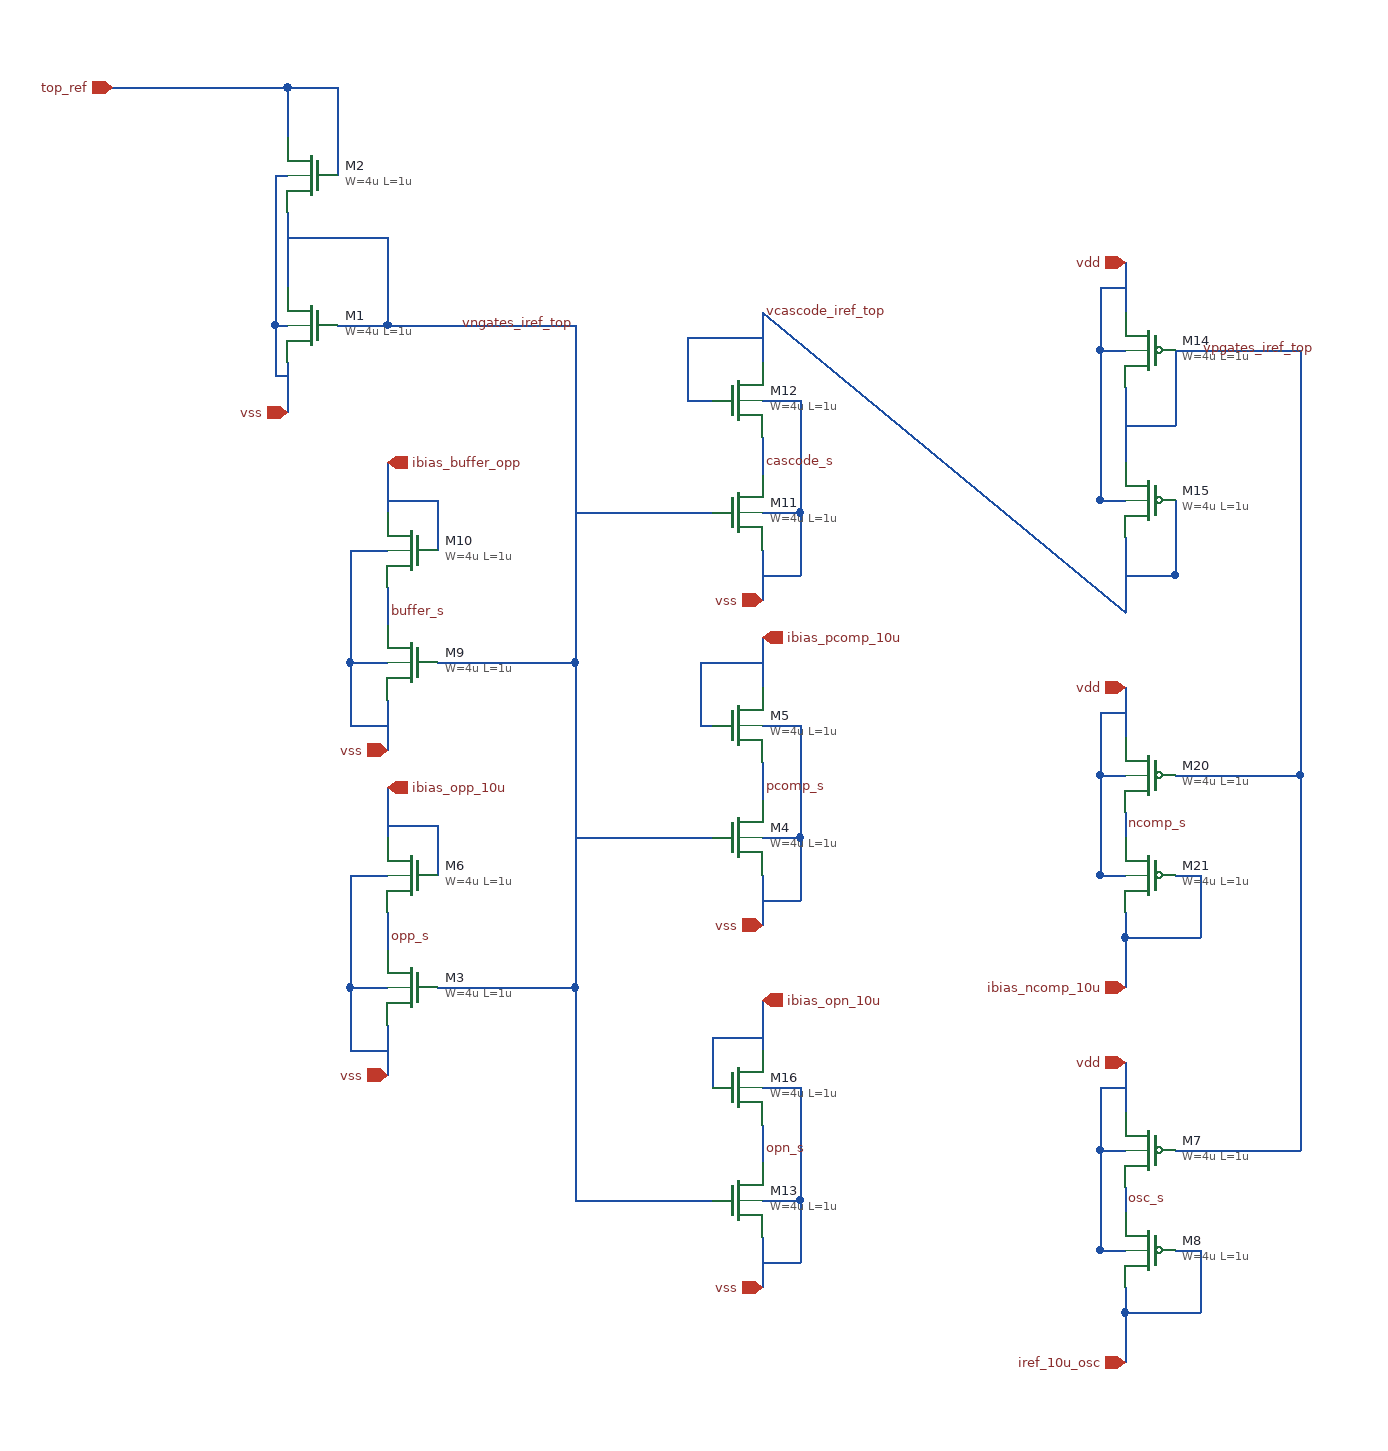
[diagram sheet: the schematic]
v {xschem version=3.4.7 file_version=1.2}
G {}
K {}
V {}
S {}
E {}
N 180 -1170 210 -1170 {lab=top_ref}
N 210 -1170 320 -1170 {lab=top_ref}
N 310 -980 320 -980 {lab=vss}
N 320 -950 320 -920 {lab=vss}
N 310 -980 310 -940 {lab=vss}
N 310 -940 320 -940 {lab=vss}
N 320 -920 320 -910 {lab=vss}
N 360 -980 400 -980 {lab=vngates_iref_top}
N 320 -1050 400 -1050 {lab=vngates_iref_top}
N 320 -1070 320 -1010 {lab=vngates_iref_top}
N 310 -1100 320 -1100 {lab=vss}
N 310 -1100 310 -980 {lab=vss}
N 320 -1170 320 -1130 {lab=top_ref}
N 360 -1170 360 -1100 {lab=top_ref}
N 320 -1170 360 -1170 {lab=top_ref}
N 700 -540 700 -500 {lab=vss}
N 700 -570 730 -570 {lab=vss}
N 730 -570 730 -520 {lab=vss}
N 700 -520 730 -520 {lab=vss}
N 700 -630 700 -600 {lab=pcomp_s}
N 620 -570 660 -570 {lab=vngates_iref_top}
N 700 -730 700 -690 {lab=ibias_pcomp_10u}
N 710 -660 730 -660 {lab=vss}
N 730 -660 730 -570 {lab=vss}
N 700 -660 710 -660 {lab=vss}
N 400 -420 400 -380 {lab=vss}
N 370 -450 400 -450 {lab=vss}
N 370 -450 370 -400 {lab=vss}
N 370 -400 400 -400 {lab=vss}
N 400 -510 400 -480 {lab=opp_s}
N 440 -450 480 -450 {lab=vngates_iref_top}
N 400 -610 400 -570 {lab=ibias_opp_10u}
N 370 -540 390 -540 {lab=vss}
N 370 -540 370 -450 {lab=vss}
N 390 -540 400 -540 {lab=vss}
N 400 -680 400 -640 {lab=vss}
N 370 -710 400 -710 {lab=vss}
N 370 -710 370 -660 {lab=vss}
N 370 -660 400 -660 {lab=vss}
N 400 -770 400 -740 {lab=buffer_s}
N 510 -710 550 -710 {lab=vngates_iref_top}
N 370 -800 390 -800 {lab=vss}
N 370 -800 370 -710 {lab=vss}
N 390 -800 400 -800 {lab=vss}
N 400 -870 400 -830 {lab=ibias_buffer_opp}
N 550 -980 550 -710 {lab=vngates_iref_top}
N 550 -710 550 -450 {lab=vngates_iref_top}
N 700 -800 700 -760 {lab=vss}
N 700 -830 730 -830 {lab=vss}
N 730 -830 730 -780 {lab=vss}
N 700 -780 730 -780 {lab=vss}
N 700 -890 700 -860 {lab=cascode_s}
N 620 -830 660 -830 {lab=vngates_iref_top}
N 710 -920 730 -920 {lab=vss}
N 730 -920 730 -830 {lab=vss}
N 700 -920 710 -920 {lab=vss}
N 700 -990 700 -940 {lab=vcascode_iref_top}
N 990 -780 1030 -780 {lab=vcascode_iref_top}
N 1030 -840 1030 -780 {lab=vcascode_iref_top}
N 970 -840 990 -840 {lab=vdd}
N 990 -900 1030 -900 {lab=vpgates_iref_top}
N 1030 -960 1030 -900 {lab=vpgates_iref_top}
N 970 -960 990 -960 {lab=vdd}
N 970 -1010 970 -960 {lab=vdd}
N 970 -1010 980 -1010 {lab=vdd}
N 980 -1010 990 -1010 {lab=vdd}
N 990 -1030 990 -990 {lab=vdd}
N 990 -930 990 -870 {lab=vpgates_iref_top}
N 970 -960 970 -890 {lab=vdd}
N 1030 -960 1130 -960 {lab=vpgates_iref_top}
N 990 -810 990 -750 {lab=vcascode_iref_top}
N 990 -780 1030 -780 {lab=vcascode_iref_top}
N 1030 -840 1030 -780 {lab=vcascode_iref_top}
N 970 -840 990 -840 {lab=vdd}
N 970 -890 970 -840 {lab=vdd}
N 990 -930 990 -870 {lab=vpgates_iref_top}
N 1130 -960 1130 -620 {lab=vpgates_iref_top}
N 970 -540 990 -540 {lab=vdd}
N 970 -620 990 -620 {lab=vdd}
N 970 -670 970 -620 {lab=vdd}
N 970 -670 980 -670 {lab=vdd}
N 980 -670 990 -670 {lab=vdd}
N 990 -690 990 -650 {lab=vdd}
N 1030 -620 1130 -620 {lab=vpgates_iref_top}
N 970 -540 990 -540 {lab=vdd}
N 990 -590 990 -580 {lab=cascode_s}
N 990 -580 990 -570 {lab=cascode_s}
N 970 -620 970 -540 {lab=vdd}
N 1030 -540 1050 -540 {lab=ibias_ncomp_10u}
N 1050 -540 1050 -490 {lab=ibias_ncomp_10u}
N 990 -490 1050 -490 {lab=ibias_ncomp_10u}
N 990 -510 990 -490 {lab=ibias_ncomp_10u}
N 990 -490 990 -450 {lab=ibias_ncomp_10u}
N 640 -920 660 -920 {lab=vcascode_iref_top}
N 640 -970 640 -920 {lab=vcascode_iref_top}
N 640 -970 700 -970 {lab=vcascode_iref_top}
N 650 -660 660 -660 {lab=ibias_pcomp_10u}
N 650 -710 650 -660 {lab=ibias_pcomp_10u}
N 650 -710 700 -710 {lab=ibias_pcomp_10u}
N 440 -840 440 -800 {lab=ibias_buffer_opp}
N 400 -840 440 -840 {lab=ibias_buffer_opp}
N 440 -580 440 -540 {lab=ibias_opp_10u}
N 400 -580 440 -580 {lab=ibias_opp_10u}
N 400 -1050 400 -980 {lab=vngates_iref_top}
N 400 -980 480 -980 {lab=vngates_iref_top}
N 500 -710 510 -710 {lab=vngates_iref_top}
N 440 -710 500 -710 {lab=vngates_iref_top}
N 480 -450 550 -450 {lab=vngates_iref_top}
N 550 -450 550 -310 {lab=vngates_iref_top}
N 550 -570 620 -570 {lab=vngates_iref_top}
N 550 -830 620 -830 {lab=vngates_iref_top}
N 480 -980 550 -980 {lab=vngates_iref_top}
N 700 -250 700 -210 {lab=vss}
N 700 -280 730 -280 {lab=vss}
N 730 -280 730 -230 {lab=vss}
N 700 -230 730 -230 {lab=vss}
N 700 -340 700 -310 {lab=opn_s}
N 620 -280 660 -280 {lab=vngates_iref_top}
N 700 -440 700 -400 {lab=ibias_opn_10u}
N 710 -370 730 -370 {lab=vss}
N 730 -370 730 -280 {lab=vss}
N 700 -370 710 -370 {lab=vss}
N 660 -410 660 -370 {lab=ibias_opn_10u}
N 660 -410 700 -410 {lab=ibias_opn_10u}
N 550 -280 620 -280 {lab=vngates_iref_top}
N 550 -300 550 -280 {lab=vngates_iref_top}
N 550 -310 550 -300 {lab=vngates_iref_top}
N 970 -240 990 -240 {lab=vdd}
N 970 -320 990 -320 {lab=vdd}
N 970 -370 970 -320 {lab=vdd}
N 970 -370 980 -370 {lab=vdd}
N 980 -370 990 -370 {lab=vdd}
N 990 -390 990 -350 {lab=vdd}
N 1030 -320 1130 -320 {lab=vpgates_iref_top}
N 970 -240 990 -240 {lab=vdd}
N 990 -290 990 -280 {lab=#net1}
N 990 -280 990 -270 {lab=#net1}
N 970 -320 970 -240 {lab=vdd}
N 1030 -240 1050 -240 {lab=iref_10u_osc}
N 1050 -240 1050 -190 {lab=iref_10u_osc}
N 990 -190 1050 -190 {lab=iref_10u_osc}
N 990 -210 990 -190 {lab=iref_10u_osc}
N 990 -190 990 -150 {lab=iref_10u_osc}
N 1130 -620 1130 -320 {lab=vpgates_iref_top}
N 700 -990 990 -750 {lab=vcascode_iref_top}
C {title.sym} 160 30 0 0 {name=l1 author="Christopher O Amankwaa"}
C {symbols/nfet_03v3.sym} 340 -980 0 1 {name=M1
L=1u
W=4u
nf=1
m=1
ad="'int((nf+1)/2) * W/nf * 0.18u'"
pd="'2*int((nf+1)/2) * (W/nf + 0.18u)'"
as="'int((nf+2)/2) * W/nf * 0.18u'"
ps="'2*int((nf+2)/2) * (W/nf + 0.18u)'"
nrd="'0.18u / W'" nrs="'0.18u / W'"
sa=0 sb=0 sd=0
model=nfet_03v3
spiceprefix=X
}
C {symbols/nfet_03v3.sym} 340 -1100 0 1 {name=M2
L=1u
W=4u
nf=1
m=1
ad="'int((nf+1)/2) * W/nf * 0.18u'"
pd="'2*int((nf+1)/2) * (W/nf + 0.18u)'"
as="'int((nf+2)/2) * W/nf * 0.18u'"
ps="'2*int((nf+2)/2) * (W/nf + 0.18u)'"
nrd="'0.18u / W'" nrs="'0.18u / W'"
sa=0 sb=0 sd=0
model=nfet_03v3
spiceprefix=X
}
C {lab_wire.sym} 550 -980 0 0 {name=p116 sig_type=std_logic lab=vngates_iref_top}
C {symbols/nfet_03v3.sym} 680 -570 0 0 {name=M4
L=1u
W=4u
nf=1
m=1
ad="'int((nf+1)/2) * W/nf * 0.18u'"
pd="'2*int((nf+1)/2) * (W/nf + 0.18u)'"
as="'int((nf+2)/2) * W/nf * 0.18u'"
ps="'2*int((nf+2)/2) * (W/nf + 0.18u)'"
nrd="'0.18u / W'" nrs="'0.18u / W'"
sa=0 sb=0 sd=0
model=nfet_03v3
spiceprefix=X
}
C {symbols/nfet_03v3.sym} 680 -660 0 0 {name=M5
L=1u
W=4u
nf=1
m=1
ad="'int((nf+1)/2) * W/nf * 0.18u'"
pd="'2*int((nf+1)/2) * (W/nf + 0.18u)'"
as="'int((nf+2)/2) * W/nf * 0.18u'"
ps="'2*int((nf+2)/2) * (W/nf + 0.18u)'"
nrd="'0.18u / W'" nrs="'0.18u / W'"
sa=0 sb=0 sd=0
model=nfet_03v3
spiceprefix=X
}
C {symbols/nfet_03v3.sym} 420 -450 0 1 {name=M3
L=1u
W=4u
nf=1
m=1
ad="'int((nf+1)/2) * W/nf * 0.18u'"
pd="'2*int((nf+1)/2) * (W/nf + 0.18u)'"
as="'int((nf+2)/2) * W/nf * 0.18u'"
ps="'2*int((nf+2)/2) * (W/nf + 0.18u)'"
nrd="'0.18u / W'" nrs="'0.18u / W'"
sa=0 sb=0 sd=0
model=nfet_03v3
spiceprefix=X
}
C {symbols/nfet_03v3.sym} 420 -540 0 1 {name=M6
L=1u
W=4u
nf=1
m=1
ad="'int((nf+1)/2) * W/nf * 0.18u'"
pd="'2*int((nf+1)/2) * (W/nf + 0.18u)'"
as="'int((nf+2)/2) * W/nf * 0.18u'"
ps="'2*int((nf+2)/2) * (W/nf + 0.18u)'"
nrd="'0.18u / W'" nrs="'0.18u / W'"
sa=0 sb=0 sd=0
model=nfet_03v3
spiceprefix=X
}
C {symbols/nfet_03v3.sym} 420 -710 0 1 {name=M9
L=1u
W=4u
nf=1
m=1
ad="'int((nf+1)/2) * W/nf * 0.18u'"
pd="'2*int((nf+1)/2) * (W/nf + 0.18u)'"
as="'int((nf+2)/2) * W/nf * 0.18u'"
ps="'2*int((nf+2)/2) * (W/nf + 0.18u)'"
nrd="'0.18u / W'" nrs="'0.18u / W'"
sa=0 sb=0 sd=0
model=nfet_03v3
spiceprefix=X
}
C {symbols/nfet_03v3.sym} 420 -800 0 1 {name=M10
L=1u
W=4u
nf=1
m=1
ad="'int((nf+1)/2) * W/nf * 0.18u'"
pd="'2*int((nf+1)/2) * (W/nf + 0.18u)'"
as="'int((nf+2)/2) * W/nf * 0.18u'"
ps="'2*int((nf+2)/2) * (W/nf + 0.18u)'"
nrd="'0.18u / W'" nrs="'0.18u / W'"
sa=0 sb=0 sd=0
model=nfet_03v3
spiceprefix=X
}
C {symbols/nfet_03v3.sym} 680 -830 0 0 {name=M11
L=1u
W=4u
nf=1
m=1
ad="'int((nf+1)/2) * W/nf * 0.18u'"
pd="'2*int((nf+1)/2) * (W/nf + 0.18u)'"
as="'int((nf+2)/2) * W/nf * 0.18u'"
ps="'2*int((nf+2)/2) * (W/nf + 0.18u)'"
nrd="'0.18u / W'" nrs="'0.18u / W'"
sa=0 sb=0 sd=0
model=nfet_03v3
spiceprefix=X
}
C {symbols/nfet_03v3.sym} 680 -920 0 0 {name=M12
L=1u
W=4u
nf=1
m=1
ad="'int((nf+1)/2) * W/nf * 0.18u'"
pd="'2*int((nf+1)/2) * (W/nf + 0.18u)'"
as="'int((nf+2)/2) * W/nf * 0.18u'"
ps="'2*int((nf+2)/2) * (W/nf + 0.18u)'"
nrd="'0.18u / W'" nrs="'0.18u / W'"
sa=0 sb=0 sd=0
model=nfet_03v3
spiceprefix=X
}
C {symbols/pfet_03v3.sym} 1010 -960 0 1 {name=M14
L=1u
W=4u
nf=1
m=1
ad="'int((nf+1)/2) * W/nf * 0.18u'"
pd="'2*int((nf+1)/2) * (W/nf + 0.18u)'"
as="'int((nf+2)/2) * W/nf * 0.18u'"
ps="'2*int((nf+2)/2) * (W/nf + 0.18u)'"
nrd="'0.18u / W'" nrs="'0.18u / W'"
sa=0 sb=0 sd=0
model=pfet_03v3
spiceprefix=X
}
C {lab_wire.sym} 700 -990 0 1 {name=p126 sig_type=std_logic lab=vcascode_iref_top}
C {lab_wire.sym} 1050 -960 0 1 {name=p127 sig_type=std_logic lab=vpgates_iref_top}
C {symbols/pfet_03v3.sym} 1010 -840 0 1 {name=M15
L=1u
W=4u
nf=1
m=1
ad="'int((nf+1)/2) * W/nf * 0.18u'"
pd="'2*int((nf+1)/2) * (W/nf + 0.18u)'"
as="'int((nf+2)/2) * W/nf * 0.18u'"
ps="'2*int((nf+2)/2) * (W/nf + 0.18u)'"
nrd="'0.18u / W'" nrs="'0.18u / W'"
sa=0 sb=0 sd=0
model=pfet_03v3
spiceprefix=X
}
C {symbols/pfet_03v3.sym} 1010 -620 0 1 {name=M20
L=1u
W=4u
nf=1
m=1
ad="'int((nf+1)/2) * W/nf * 0.18u'"
pd="'2*int((nf+1)/2) * (W/nf + 0.18u)'"
as="'int((nf+2)/2) * W/nf * 0.18u'"
ps="'2*int((nf+2)/2) * (W/nf + 0.18u)'"
nrd="'0.18u / W'" nrs="'0.18u / W'"
sa=0 sb=0 sd=0
model=pfet_03v3
spiceprefix=X
}
C {symbols/pfet_03v3.sym} 1010 -540 0 1 {name=M21
L=1u
W=4u
nf=1
m=1
ad="'int((nf+1)/2) * W/nf * 0.18u'"
pd="'2*int((nf+1)/2) * (W/nf + 0.18u)'"
as="'int((nf+2)/2) * W/nf * 0.18u'"
ps="'2*int((nf+2)/2) * (W/nf + 0.18u)'"
nrd="'0.18u / W'" nrs="'0.18u / W'"
sa=0 sb=0 sd=0
model=pfet_03v3
spiceprefix=X
}
C {symbols/nfet_03v3.sym} 680 -280 0 0 {name=M13
L=1u
W=4u
nf=1
m=1
ad="'int((nf+1)/2) * W/nf * 0.18u'"
pd="'2*int((nf+1)/2) * (W/nf + 0.18u)'"
as="'int((nf+2)/2) * W/nf * 0.18u'"
ps="'2*int((nf+2)/2) * (W/nf + 0.18u)'"
nrd="'0.18u / W'" nrs="'0.18u / W'"
sa=0 sb=0 sd=0
model=nfet_03v3
spiceprefix=X
}
C {symbols/nfet_03v3.sym} 680 -370 0 0 {name=M16
L=1u
W=4u
nf=1
m=1
ad="'int((nf+1)/2) * W/nf * 0.18u'"
pd="'2*int((nf+1)/2) * (W/nf + 0.18u)'"
as="'int((nf+2)/2) * W/nf * 0.18u'"
ps="'2*int((nf+2)/2) * (W/nf + 0.18u)'"
nrd="'0.18u / W'" nrs="'0.18u / W'"
sa=0 sb=0 sd=0
model=nfet_03v3
spiceprefix=X
}
C {symbols/pfet_03v3.sym} 1010 -320 0 1 {name=M7
L=1u
W=4u
nf=1
m=1
ad="'int((nf+1)/2) * W/nf * 0.18u'"
pd="'2*int((nf+1)/2) * (W/nf + 0.18u)'"
as="'int((nf+2)/2) * W/nf * 0.18u'"
ps="'2*int((nf+2)/2) * (W/nf + 0.18u)'"
nrd="'0.18u / W'" nrs="'0.18u / W'"
sa=0 sb=0 sd=0
model=pfet_03v3
spiceprefix=X
}
C {symbols/pfet_03v3.sym} 1010 -240 0 1 {name=M8
L=1u
W=4u
nf=1
m=1
ad="'int((nf+1)/2) * W/nf * 0.18u'"
pd="'2*int((nf+1)/2) * (W/nf + 0.18u)'"
as="'int((nf+2)/2) * W/nf * 0.18u'"
ps="'2*int((nf+2)/2) * (W/nf + 0.18u)'"
nrd="'0.18u / W'" nrs="'0.18u / W'"
sa=0 sb=0 sd=0
model=pfet_03v3
spiceprefix=X
}
C {ipin.sym} 180 -1170 0 0 {name=p1 lab=top_ref}
C {ipin.sym} 320 -910 0 0 {name=p2 lab=vss}
C {opin.sym} 400 -610 2 0 {name=p3 lab=ibias_opp_10u}
C {ipin.sym} 400 -380 0 0 {name=p4 lab=vss}
C {opin.sym} 400 -870 2 0 {name=p5 lab=ibias_buffer_opp}
C {ipin.sym} 700 -500 0 0 {name=p6 lab=vss}
C {ipin.sym} 700 -760 0 0 {name=p7 lab=vss}
C {ipin.sym} 700 -210 0 0 {name=p8 lab=vss}
C {ipin.sym} 990 -390 0 0 {name=p9 lab=vdd}
C {ipin.sym} 990 -690 0 0 {name=p10 lab=vdd}
C {ipin.sym} 990 -1030 0 0 {name=p11 lab=vdd}
C {opin.sym} 700 -730 0 0 {name=p12 lab=ibias_pcomp_10u}
C {opin.sym} 700 -440 0 0 {name=p13 lab=ibias_opn_10u}
C {opin.sym} 990 -450 0 1 {name=p14 lab=ibias_ncomp_10u}
C {opin.sym} 990 -150 0 1 {name=p15 lab=iref_10u_osc}
C {ipin.sym} 400 -640 0 0 {name=p16 lab=vss}
C {lab_wire.sym} 400 -750 0 1 {name=p17 sig_type=std_logic lab=buffer_s}
C {lab_wire.sym} 400 -490 0 1 {name=p18 sig_type=std_logic lab=opp_s}
C {lab_wire.sym} 700 -320 0 1 {name=p19 sig_type=std_logic lab=opn_s}
C {lab_wire.sym} 700 -610 0 1 {name=p20 sig_type=std_logic lab=pcomp_s}
C {lab_wire.sym} 700 -870 0 1 {name=p21 sig_type=std_logic lab=cascode_s}
C {lab_wire.sym} 990 -580 0 1 {name=p22 sig_type=std_logic lab=ncomp_s}
C {lab_wire.sym} 990 -280 0 1 {name=p23 sig_type=std_logic lab=osc_s}
